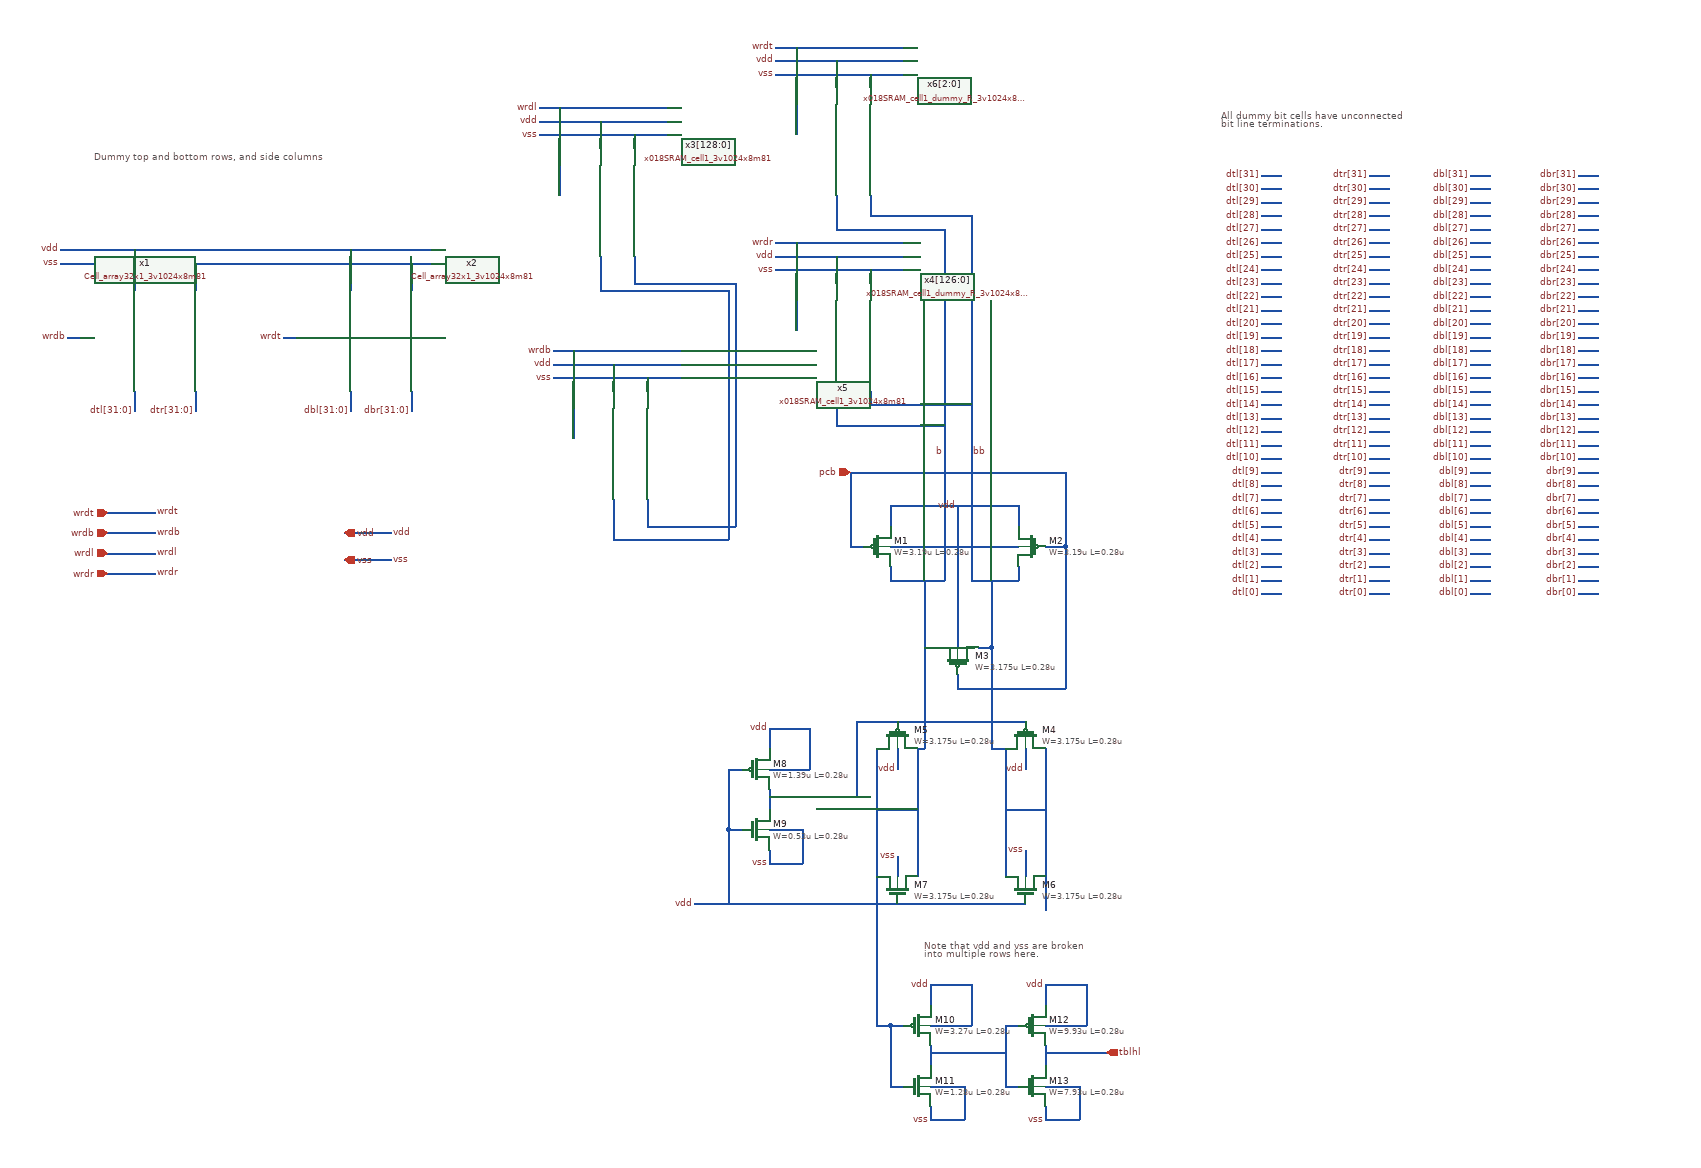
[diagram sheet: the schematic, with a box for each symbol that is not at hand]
v {xschem version=3.4.6 file_version=1.2}
G {}
K {}
V {}
S {}
E {}
T {Dummy top and bottom rows, and side columns} -160 -200 0 0 0.4 0.4 {}
T {Note that vdd and vss are broken
into multiple rows here.} 1070 970 0 0 0.3 0.3 {}
T {All dummy bit cells have unconnected
bit line terminations.} 1510 -260 0 0 0.3 0.3 {}
N 310 -30 310 10 {lab=vss}
N 220 -50 220 10 {lab=vdd}
N -10 -30 -10 10 {lab=vss}
N -100 -50 -100 10 {lab=vdd}
N -200 80 -180 80 {lab=wrdb}
N 120 80 140 80 {lab=wrdt}
N -100 160 -100 190 {lab=dtl[31:0]}
N -10 160 -10 190 {lab=dtr[31:0]}
N 220 160 220 190 {lab=dbl[31:0]}
N 310 160 310 190 {lab=dbr[31:0]}
N -140 400 -70 400 {lab=wrdl}
N 210 370 280 370 {lab=vdd}
N 210 410 280 410 {lab=vss}
N -210 -50 340 -50 {lab=vdd}
N -210 -30 340 -30 {lab=vss}
N 530 -260 530 -130 {lab=wrdl}
N 590 -240 590 -200 {lab=vdd}
N 590 -40 590 0 {lab=#net1}
N 640 -40 640 0 {lab=#net2}
N 500 -220 690 -220 {lab=vss}
N 640 -220 640 -200 {lab=vss}
N 500 -240 690 -240 {lab=vdd}
N 500 -260 690 -260 {lab=wrdl}
N 880 -60 880 70 {lab=wrdr}
N 940 -40 940 0 {lab=vdd}
N 850 -20 1040 -20 {lab=vss}
N 990 -20 990 0 {lab=vss}
N 850 -40 1040 -40 {lab=vdd}
N 850 -60 1040 -60 {lab=wrdr}
N -140 370 -70 370 {lab=wrdb}
N -140 340 -70 340 {lab=wrdt}
N 880 -350 880 -220 {lab=wrdt}
N 940 -330 940 -290 {lab=vdd}
N 850 -310 1040 -310 {lab=vss}
N 990 -310 990 -290 {lab=vss}
N 850 -330 1040 -330 {lab=vdd}
N 850 -350 1040 -350 {lab=wrdt}
N -140 430 -70 430 {lab=wrdr}
N 550 100 550 230 {lab=wrdb}
N 610 120 610 160 {lab=vdd}
N 610 320 610 360 {lab=#net1}
N 660 320 660 360 {lab=#net2}
N 520 140 710 140 {lab=vss}
N 660 140 660 160 {lab=vss}
N 520 120 710 120 {lab=vdd}
N 520 100 710 100 {lab=wrdb}
N 990 -130 990 -100 {lab=bb}
N 990 -100 1140 -100 {lab=bb}
N 1140 -100 1140 300 {lab=bb}
N 940 -130 940 -80 {lab=b}
N 940 -80 1100 -80 {lab=b}
N 1100 -80 1100 300 {lab=b}
N 990 160 990 180 {lab=bb}
N 990 180 1140 180 {lab=bb}
N 940 160 940 210 {lab=b}
N 940 210 1100 210 {lab=b}
N 1020 390 1210 390 {lab=vdd}
N 1210 420 1210 440 {lab=bb}
N 1140 440 1210 440 {lab=bb}
N 1020 420 1020 440 {lab=b}
N 1020 440 1100 440 {lab=b}
N 1210 330 1210 360 {lab=vdd}
N 1020 330 1210 330 {lab=vdd}
N 1020 330 1020 360 {lab=vdd}
N 1120 330 1120 390 {lab=vdd}
N 1250 390 1280 390 {lab=pcb}
N 1280 280 1280 390 {lab=pcb}
N 960 280 1280 280 {lab=pcb}
N 960 390 980 390 {lab=pcb}
N 960 280 960 390 {lab=pcb}
N 1140 300 1140 440 {lab=bb}
N 1100 300 1100 440 {lab=b}
N 1150 540 1170 540 {lab=bb}
N 1170 440 1170 540 {lab=bb}
N 1120 580 1120 600 {lab=pcb}
N 1120 600 1280 600 {lab=pcb}
N 1280 390 1280 600 {lab=pcb}
N 1120 390 1120 540 {lab=vdd}
N 1190 690 1190 880 {lab=bb}
N 1250 690 1250 880 {lab=bb}
N 1060 690 1060 880 {lab=b}
N 1000 690 1000 880 {lab=b}
N 1060 690 1070 690 {lab=b}
N 1170 540 1170 690 {lab=bb}
N 1170 690 1190 690 {lab=bb}
N 1070 440 1070 690 {lab=b}
N 1070 540 1090 540 {lab=b}
N 1190 780 1250 780 {lab=bb}
N 1000 880 1000 1020 {lab=b}
N 840 660 840 690 {lab=vdd}
N 840 660 900 660 {lab=vdd}
N 900 660 900 720 {lab=vdd}
N 840 720 900 720 {lab=vdd}
N 840 840 840 860 {lab=vss}
N 840 860 890 860 {lab=vss}
N 890 810 890 860 {lab=vss}
N 840 810 890 810 {lab=vss}
N 840 750 840 780 {lab=#net3}
N 780 810 800 810 {lab=vdd}
N 780 720 780 810 {lab=vdd}
N 780 720 800 720 {lab=vdd}
N 840 760 970 760 {lab=#net3}
N 970 650 970 760 {lab=#net3}
N 970 650 1220 650 {lab=#net3}
N 730 920 1220 920 {lab=vdd}
N 780 810 780 920 {lab=vdd}
N 1250 880 1250 930 {lab=bb}
N 1030 850 1030 880 {lab=vss}
N 1220 840 1220 880 {lab=vss}
N 1220 690 1220 720 {lab=vdd}
N 1030 690 1030 720 {lab=vdd}
N 1080 1040 1080 1070 {lab=vdd}
N 1080 1040 1140 1040 {lab=vdd}
N 1140 1040 1140 1100 {lab=vdd}
N 1080 1100 1140 1100 {lab=vdd}
N 1080 1220 1080 1240 {lab=vss}
N 1080 1240 1130 1240 {lab=vss}
N 1130 1190 1130 1240 {lab=vss}
N 1080 1190 1130 1190 {lab=vss}
N 1080 1130 1080 1160 {lab=#net4}
N 1020 1190 1040 1190 {lab=b}
N 1020 1100 1020 1190 {lab=b}
N 1020 1100 1040 1100 {lab=b}
N 1250 1040 1250 1070 {lab=vdd}
N 1250 1040 1310 1040 {lab=vdd}
N 1310 1040 1310 1100 {lab=vdd}
N 1250 1100 1310 1100 {lab=vdd}
N 1250 1220 1250 1240 {lab=vss}
N 1250 1240 1300 1240 {lab=vss}
N 1300 1190 1300 1240 {lab=vss}
N 1250 1190 1300 1190 {lab=vss}
N 1250 1130 1250 1160 {lab=tblhl}
N 1190 1190 1210 1190 {lab=#net4}
N 1190 1100 1190 1190 {lab=#net4}
N 1190 1100 1210 1100 {lab=#net4}
N 1080 1140 1190 1140 {lab=#net4}
N 1000 1020 1000 1100 {lab=b}
N 1000 1100 1020 1100 {lab=b}
N 1250 1140 1340 1140 {lab=tblhl}
N 1570 -160 1600 -160 {lab=dtl[31]}
N 1570 -140 1600 -140 {lab=dtl[30]}
N 1570 -120 1600 -120 {lab=dtl[29]}
N 1570 -100 1600 -100 {lab=dtl[28]}
N 1570 -80 1600 -80 {lab=dtl[27]}
N 1570 -60 1600 -60 {lab=dtl[26]}
N 1570 -40 1600 -40 {lab=dtl[25]}
N 1570 -20 1600 -20 {lab=dtl[24]}
N 1570 0 1600 0 {lab=dtl[23]}
N 1570 20 1600 20 {lab=dtl[22]}
N 1570 40 1600 40 {lab=dtl[21]}
N 1570 60 1600 60 {lab=dtl[20]}
N 1570 80 1600 80 {lab=dtl[19]}
N 1570 100 1600 100 {lab=dtl[18]}
N 1570 120 1600 120 {lab=dtl[17]}
N 1570 140 1600 140 {lab=dtl[16]}
N 1570 160 1600 160 {lab=dtl[15]}
N 1570 180 1600 180 {lab=dtl[14]}
N 1570 200 1600 200 {lab=dtl[13]}
N 1570 220 1600 220 {lab=dtl[12]}
N 1570 240 1600 240 {lab=dtl[11]}
N 1570 260 1600 260 {lab=dtl[10]}
N 1570 280 1600 280 {lab=dtl[9]}
N 1570 300 1600 300 {lab=dtl[8]}
N 1570 320 1600 320 {lab=dtl[7]}
N 1570 340 1600 340 {lab=dtl[6]}
N 1570 360 1600 360 {lab=dtl[5]}
N 1570 380 1600 380 {lab=dtl[4]}
N 1570 400 1600 400 {lab=dtl[3]}
N 1570 420 1600 420 {lab=dtl[2]}
N 1570 440 1600 440 {lab=dtl[1]}
N 1570 460 1600 460 {lab=dtl[0]}
N 1730 -160 1760 -160 {lab=dtr[31]}
N 1730 -140 1760 -140 {lab=dtr[30]}
N 1730 -120 1760 -120 {lab=dtr[29]}
N 1730 -100 1760 -100 {lab=dtr[28]}
N 1730 -80 1760 -80 {lab=dtr[27]}
N 1730 -60 1760 -60 {lab=dtr[26]}
N 1730 -40 1760 -40 {lab=dtr[25]}
N 1730 -20 1760 -20 {lab=dtr[24]}
N 1730 0 1760 0 {lab=dtr[23]}
N 1730 20 1760 20 {lab=dtr[22]}
N 1730 40 1760 40 {lab=dtr[21]}
N 1730 60 1760 60 {lab=dtr[20]}
N 1730 80 1760 80 {lab=dtr[19]}
N 1730 100 1760 100 {lab=dtr[18]}
N 1730 120 1760 120 {lab=dtr[17]}
N 1730 140 1760 140 {lab=dtr[16]}
N 1730 160 1760 160 {lab=dtr[15]}
N 1730 180 1760 180 {lab=dtr[14]}
N 1730 200 1760 200 {lab=dtr[13]}
N 1730 220 1760 220 {lab=dtr[12]}
N 1730 240 1760 240 {lab=dtr[11]}
N 1730 260 1760 260 {lab=dtr[10]}
N 1730 280 1760 280 {lab=dtr[9]}
N 1730 300 1760 300 {lab=dtr[8]}
N 1730 320 1760 320 {lab=dtr[7]}
N 1730 340 1760 340 {lab=dtr[6]}
N 1730 360 1760 360 {lab=dtr[5]}
N 1730 380 1760 380 {lab=dtr[4]}
N 1730 400 1760 400 {lab=dtr[3]}
N 1730 420 1760 420 {lab=dtr[2]}
N 1730 440 1760 440 {lab=dtr[1]}
N 1730 460 1760 460 {lab=dtr[0]}
N 1880 -160 1910 -160 {lab=dbl[31]}
N 1880 -140 1910 -140 {lab=dbl[30]}
N 1880 -120 1910 -120 {lab=dbl[29]}
N 1880 -100 1910 -100 {lab=dbl[28]}
N 1880 -80 1910 -80 {lab=dbl[27]}
N 1880 -60 1910 -60 {lab=dbl[26]}
N 1880 -40 1910 -40 {lab=dbl[25]}
N 1880 -20 1910 -20 {lab=dbl[24]}
N 1880 0 1910 0 {lab=dbl[23]}
N 1880 20 1910 20 {lab=dbl[22]}
N 1880 40 1910 40 {lab=dbl[21]}
N 1880 60 1910 60 {lab=dbl[20]}
N 1880 80 1910 80 {lab=dbl[19]}
N 1880 100 1910 100 {lab=dbl[18]}
N 1880 120 1910 120 {lab=dbl[17]}
N 1880 140 1910 140 {lab=dbl[16]}
N 1880 160 1910 160 {lab=dbl[15]}
N 1880 180 1910 180 {lab=dbl[14]}
N 1880 200 1910 200 {lab=dbl[13]}
N 1880 220 1910 220 {lab=dbl[12]}
N 1880 240 1910 240 {lab=dbl[11]}
N 1880 260 1910 260 {lab=dbl[10]}
N 1880 280 1910 280 {lab=dbl[9]}
N 1880 300 1910 300 {lab=dbl[8]}
N 1880 320 1910 320 {lab=dbl[7]}
N 1880 340 1910 340 {lab=dbl[6]}
N 1880 360 1910 360 {lab=dbl[5]}
N 1880 380 1910 380 {lab=dbl[4]}
N 1880 400 1910 400 {lab=dbl[3]}
N 1880 420 1910 420 {lab=dbl[2]}
N 1880 440 1910 440 {lab=dbl[1]}
N 1880 460 1910 460 {lab=dbl[0]}
N 2040 -160 2070 -160 {lab=dbr[31]}
N 2040 -140 2070 -140 {lab=dbr[30]}
N 2040 -120 2070 -120 {lab=dbr[29]}
N 2040 -100 2070 -100 {lab=dbr[28]}
N 2040 -80 2070 -80 {lab=dbr[27]}
N 2040 -60 2070 -60 {lab=dbr[26]}
N 2040 -40 2070 -40 {lab=dbr[25]}
N 2040 -20 2070 -20 {lab=dbr[24]}
N 2040 0 2070 0 {lab=dbr[23]}
N 2040 20 2070 20 {lab=dbr[22]}
N 2040 40 2070 40 {lab=dbr[21]}
N 2040 60 2070 60 {lab=dbr[20]}
N 2040 80 2070 80 {lab=dbr[19]}
N 2040 100 2070 100 {lab=dbr[18]}
N 2040 120 2070 120 {lab=dbr[17]}
N 2040 140 2070 140 {lab=dbr[16]}
N 2040 160 2070 160 {lab=dbr[15]}
N 2040 180 2070 180 {lab=dbr[14]}
N 2040 200 2070 200 {lab=dbr[13]}
N 2040 220 2070 220 {lab=dbr[12]}
N 2040 240 2070 240 {lab=dbr[11]}
N 2040 260 2070 260 {lab=dbr[10]}
N 2040 280 2070 280 {lab=dbr[9]}
N 2040 300 2070 300 {lab=dbr[8]}
N 2040 320 2070 320 {lab=dbr[7]}
N 2040 340 2070 340 {lab=dbr[6]}
N 2040 360 2070 360 {lab=dbr[5]}
N 2040 380 2070 380 {lab=dbr[4]}
N 2040 400 2070 400 {lab=dbr[3]}
N 2040 420 2070 420 {lab=dbr[2]}
N 2040 440 2070 440 {lab=dbr[1]}
N 2040 460 2070 460 {lab=dbr[0]}
N 640 0 790 -0 {lab=#net2}
N 790 -0 790 360 {lab=#net2}
N 660 360 790 360 {lab=#net2}
N 590 0 590 10 {lab=#net1}
N 590 10 780 10 {lab=#net1}
N 780 10 780 380 {lab=#net1}
N 610 380 780 380 {lab=#net1}
N 610 360 610 380 {lab=#net1}
N 1000 780 1060 780 {lab=b}
C {Cell_array32x1_3v1024x8m81.sym} -50 80 0 0 {name=x1}
C {Cell_array32x1_3v1024x8m81.sym} 270 80 0 0 {name=x2}
C {lab_pin.sym} -100 190 3 0 {name=p1 sig_type=std_logic lab=dtl[31:0]}
C {lab_pin.sym} -10 190 3 0 {name=p2 sig_type=std_logic lab=dtr[31:0]}
C {lab_pin.sym} 220 190 3 0 {name=p3 sig_type=std_logic lab=dbl[31:0]}
C {lab_pin.sym} 310 190 3 0 {name=p4 sig_type=std_logic lab=dbr[31:0]}
C {lab_pin.sym} -210 -50 0 0 {name=p97 sig_type=std_logic lab=vdd}
C {lab_pin.sym} -210 -30 0 0 {name=p98 sig_type=std_logic lab=vss}
C {ipin.sym} -140 400 0 0 {name=p105 lab=wrdl}
C {iopin.sym} 210 370 0 1 {name=p108 lab=vdd}
C {iopin.sym} 210 410 0 1 {name=p109 lab=vss}
C {lab_pin.sym} 280 410 0 1 {name=p110 sig_type=std_logic lab=vss}
C {lab_pin.sym} 280 370 0 1 {name=p111 sig_type=std_logic lab=vdd}
C {lab_pin.sym} -70 400 0 1 {name=p114 sig_type=std_logic lab=wrdl}
C {x018SRAM_cell1_3v1024x8m81.sym} 680 -150 0 0 {name=x3[128:0]}
C {lab_pin.sym} 500 -220 0 0 {name=p5 sig_type=std_logic lab=vss}
C {lab_pin.sym} 500 -240 0 0 {name=p6 sig_type=std_logic lab=vdd}
C {lab_pin.sym} 500 -260 0 0 {name=p9 sig_type=std_logic lab=wrdl}
C {lab_pin.sym} -200 80 0 0 {name=p10 sig_type=std_logic lab=wrdb}
C {lab_pin.sym} 850 -20 0 0 {name=p19 sig_type=std_logic lab=vss}
C {lab_pin.sym} 850 -40 0 0 {name=p20 sig_type=std_logic lab=vdd}
C {lab_pin.sym} 850 -60 0 0 {name=p23 sig_type=std_logic lab=wrdr}
C {x018SRAM_cell1_dummy_R_3v1024x8m81.sym} 1030 50 0 0 {name=x4[126:0]}
C {lab_pin.sym} 120 80 0 0 {name=p24 sig_type=std_logic lab=wrdt}
C {ipin.sym} -140 370 0 0 {name=p25 lab=wrdb}
C {lab_pin.sym} -70 370 0 1 {name=p26 sig_type=std_logic lab=wrdb}
C {ipin.sym} -140 340 0 0 {name=p27 lab=wrdt}
C {lab_pin.sym} -70 340 0 1 {name=p28 sig_type=std_logic lab=wrdt}
C {lab_pin.sym} 850 -310 0 0 {name=p21 sig_type=std_logic lab=vss}
C {lab_pin.sym} 850 -330 0 0 {name=p22 sig_type=std_logic lab=vdd}
C {lab_pin.sym} 850 -350 0 0 {name=p29 sig_type=std_logic lab=wrdt}
C {x018SRAM_cell1_dummy_R_3v1024x8m81.sym} 1030 -240 0 0 {name=x6[2:0]}
C {ipin.sym} -140 430 0 0 {name=p30 lab=wrdr}
C {lab_pin.sym} -70 430 0 1 {name=p31 sig_type=std_logic lab=wrdr}
C {x018SRAM_cell1_3v1024x8m81.sym} 700 210 0 0 {name=x5}
C {lab_pin.sym} 520 140 0 0 {name=p32 sig_type=std_logic lab=vss}
C {lab_pin.sym} 520 120 0 0 {name=p33 sig_type=std_logic lab=vdd}
C {lab_pin.sym} 520 100 0 0 {name=p36 sig_type=std_logic lab=wrdb}
C {ipin.sym} 960 280 0 0 {name=p37 lab=pcb}
C {lab_pin.sym} 1100 250 0 0 {name=p38 sig_type=std_logic lab=b}
C {lab_pin.sym} 1140 250 0 1 {name=p39 sig_type=std_logic lab=bb}
C {symbols/pfet_03v3.sym} 1000 390 0 0 {name=M1
L=0.28u
W=3.19u
nf=2
m=1
ad="'int((nf+1)/2) * W/nf * 0.18u'"
pd="'2*int((nf+1)/2) * (W/nf + 0.18u)'"
as="'int((nf+2)/2) * W/nf * 0.18u'"
ps="'2*int((nf+2)/2) * (W/nf + 0.18u)'"
nrd="'0.18u / W'" nrs="'0.18u / W'"
sa=0 sb=0 sd=0
model=pfet_03v3
spiceprefix=X
}
C {symbols/pfet_03v3.sym} 1230 390 0 1 {name=M2
L=0.28u
W=3.19u
nf=2
m=1
ad="'int((nf+1)/2) * W/nf * 0.18u'"
pd="'2*int((nf+1)/2) * (W/nf + 0.18u)'"
as="'int((nf+2)/2) * W/nf * 0.18u'"
ps="'2*int((nf+2)/2) * (W/nf + 0.18u)'"
nrd="'0.18u / W'" nrs="'0.18u / W'"
sa=0 sb=0 sd=0
model=pfet_03v3
spiceprefix=X
}
C {lab_pin.sym} 1120 330 1 0 {name=p40 sig_type=std_logic lab=vdd}
C {symbols/pfet_03v3.sym} 1120 560 3 0 {name=M3
L=0.28u
W=3.175u
nf=1
m=1
ad="'int((nf+1)/2) * W/nf * 0.18u'"
pd="'2*int((nf+1)/2) * (W/nf + 0.18u)'"
as="'int((nf+2)/2) * W/nf * 0.18u'"
ps="'2*int((nf+2)/2) * (W/nf + 0.18u)'"
nrd="'0.18u / W'" nrs="'0.18u / W'"
sa=0 sb=0 sd=0
model=pfet_03v3
spiceprefix=X
}
C {symbols/pfet_03v3.sym} 1220 670 3 1 {name=M4
L=0.28u
W=3.175u
nf=1
m=1
ad="'int((nf+1)/2) * W/nf * 0.18u'"
pd="'2*int((nf+1)/2) * (W/nf + 0.18u)'"
as="'int((nf+2)/2) * W/nf * 0.18u'"
ps="'2*int((nf+2)/2) * (W/nf + 0.18u)'"
nrd="'0.18u / W'" nrs="'0.18u / W'"
sa=0 sb=0 sd=0
model=pfet_03v3
spiceprefix=X
}
C {symbols/pfet_03v3.sym} 1030 670 3 1 {name=M5
L=0.28u
W=3.175u
nf=1
m=1
ad="'int((nf+1)/2) * W/nf * 0.18u'"
pd="'2*int((nf+1)/2) * (W/nf + 0.18u)'"
as="'int((nf+2)/2) * W/nf * 0.18u'"
ps="'2*int((nf+2)/2) * (W/nf + 0.18u)'"
nrd="'0.18u / W'" nrs="'0.18u / W'"
sa=0 sb=0 sd=0
model=pfet_03v3
spiceprefix=X
}
C {symbols/nfet_03v3.sym} 1220 900 3 0 {name=M6
L=0.28u
W=3.175u
nf=1
m=1
ad="'int((nf+1)/2) * W/nf * 0.18u'"
pd="'2*int((nf+1)/2) * (W/nf + 0.18u)'"
as="'int((nf+2)/2) * W/nf * 0.18u'"
ps="'2*int((nf+2)/2) * (W/nf + 0.18u)'"
nrd="'0.18u / W'" nrs="'0.18u / W'"
sa=0 sb=0 sd=0
model=nfet_03v3
spiceprefix=X
}
C {symbols/nfet_03v3.sym} 1030 900 3 0 {name=M7
L=0.28u
W=3.175u
nf=1
m=1
ad="'int((nf+1)/2) * W/nf * 0.18u'"
pd="'2*int((nf+1)/2) * (W/nf + 0.18u)'"
as="'int((nf+2)/2) * W/nf * 0.18u'"
ps="'2*int((nf+2)/2) * (W/nf + 0.18u)'"
nrd="'0.18u / W'" nrs="'0.18u / W'"
sa=0 sb=0 sd=0
model=nfet_03v3
spiceprefix=X
}
C {lab_pin.sym} 730 920 0 0 {name=p41 sig_type=std_logic lab=vdd}
C {symbols/pfet_03v3.sym} 820 720 2 1 {name=M8
L=0.28u
W=1.39u
nf=2
m=1
ad="'int((nf+1)/2) * W/nf * 0.18u'"
pd="'2*int((nf+1)/2) * (W/nf + 0.18u)'"
as="'int((nf+2)/2) * W/nf * 0.18u'"
ps="'2*int((nf+2)/2) * (W/nf + 0.18u)'"
nrd="'0.18u / W'" nrs="'0.18u / W'"
sa=0 sb=0 sd=0
model=pfet_03v3
spiceprefix=X
}
C {symbols/nfet_03v3.sym} 820 810 0 0 {name=M9
L=0.28u
W=0.53u
nf=2
m=1
ad="'int((nf+1)/2) * W/nf * 0.18u'"
pd="'2*int((nf+1)/2) * (W/nf + 0.18u)'"
as="'int((nf+2)/2) * W/nf * 0.18u'"
ps="'2*int((nf+2)/2) * (W/nf + 0.18u)'"
nrd="'0.18u / W'" nrs="'0.18u / W'"
sa=0 sb=0 sd=0
model=nfet_03v3
spiceprefix=X
}
C {lab_pin.sym} 840 660 0 0 {name=p42 sig_type=std_logic lab=vdd}
C {lab_pin.sym} 840 860 0 0 {name=p43 sig_type=std_logic lab=vss}
C {noconn.sym} 1250 930 3 0 {name=l1}
C {lab_pin.sym} 1030 720 3 0 {name=p44 sig_type=std_logic lab=vdd}
C {lab_pin.sym} 1220 720 3 0 {name=p45 sig_type=std_logic lab=vdd}
C {lab_pin.sym} 1030 850 1 0 {name=p46 sig_type=std_logic lab=vss}
C {lab_pin.sym} 1220 840 1 0 {name=p47 sig_type=std_logic lab=vss}
C {symbols/pfet_03v3.sym} 1060 1100 2 1 {name=M10
L=0.28u
W=3.27u
nf=2
m=1
ad="'int((nf+1)/2) * W/nf * 0.18u'"
pd="'2*int((nf+1)/2) * (W/nf + 0.18u)'"
as="'int((nf+2)/2) * W/nf * 0.18u'"
ps="'2*int((nf+2)/2) * (W/nf + 0.18u)'"
nrd="'0.18u / W'" nrs="'0.18u / W'"
sa=0 sb=0 sd=0
model=pfet_03v3
spiceprefix=X
}
C {symbols/nfet_03v3.sym} 1060 1190 0 0 {name=M11
L=0.28u
W=1.28u
nf=2
m=1
ad="'int((nf+1)/2) * W/nf * 0.18u'"
pd="'2*int((nf+1)/2) * (W/nf + 0.18u)'"
as="'int((nf+2)/2) * W/nf * 0.18u'"
ps="'2*int((nf+2)/2) * (W/nf + 0.18u)'"
nrd="'0.18u / W'" nrs="'0.18u / W'"
sa=0 sb=0 sd=0
model=nfet_03v3
spiceprefix=X
}
C {lab_pin.sym} 1080 1040 0 0 {name=p48 sig_type=std_logic lab=vdd}
C {lab_pin.sym} 1080 1240 0 0 {name=p49 sig_type=std_logic lab=vss}
C {symbols/pfet_03v3.sym} 1230 1100 2 1 {name=M12
L=0.28u
W=9.93u
nf=2
m=1
ad="'int((nf+1)/2) * W/nf * 0.18u'"
pd="'2*int((nf+1)/2) * (W/nf + 0.18u)'"
as="'int((nf+2)/2) * W/nf * 0.18u'"
ps="'2*int((nf+2)/2) * (W/nf + 0.18u)'"
nrd="'0.18u / W'" nrs="'0.18u / W'"
sa=0 sb=0 sd=0
model=pfet_03v3
spiceprefix=X
}
C {symbols/nfet_03v3.sym} 1230 1190 0 0 {name=M13
L=0.28u
W=7.93u
nf=2
m=1
ad="'int((nf+1)/2) * W/nf * 0.18u'"
pd="'2*int((nf+1)/2) * (W/nf + 0.18u)'"
as="'int((nf+2)/2) * W/nf * 0.18u'"
ps="'2*int((nf+2)/2) * (W/nf + 0.18u)'"
nrd="'0.18u / W'" nrs="'0.18u / W'"
sa=0 sb=0 sd=0
model=nfet_03v3
spiceprefix=X
}
C {lab_pin.sym} 1250 1040 0 0 {name=p50 sig_type=std_logic lab=vdd}
C {lab_pin.sym} 1250 1240 0 0 {name=p51 sig_type=std_logic lab=vss}
C {opin.sym} 1340 1140 0 0 {name=p52 lab=tblhl}
C {noconn.sym} 1600 -160 0 1 {name=l4}
C {noconn.sym} 1600 -140 0 1 {name=l5}
C {noconn.sym} 1600 -120 0 1 {name=l6}
C {noconn.sym} 1600 -100 0 1 {name=l7}
C {noconn.sym} 1600 -80 0 1 {name=l8}
C {noconn.sym} 1600 -60 0 1 {name=l9}
C {noconn.sym} 1600 -40 0 1 {name=l10}
C {noconn.sym} 1600 -20 0 1 {name=l11}
C {noconn.sym} 1600 0 0 1 {name=l12}
C {noconn.sym} 1600 20 0 1 {name=l13}
C {noconn.sym} 1600 40 0 1 {name=l14}
C {noconn.sym} 1600 60 0 1 {name=l15}
C {noconn.sym} 1600 80 0 1 {name=l16}
C {noconn.sym} 1600 100 0 1 {name=l17}
C {noconn.sym} 1600 120 0 1 {name=l18}
C {noconn.sym} 1600 140 0 1 {name=l19}
C {noconn.sym} 1600 160 0 1 {name=l20}
C {noconn.sym} 1600 180 0 1 {name=l21}
C {noconn.sym} 1600 200 0 1 {name=l22}
C {noconn.sym} 1600 220 0 1 {name=l23}
C {noconn.sym} 1600 240 0 1 {name=l24}
C {noconn.sym} 1600 260 0 1 {name=l25}
C {noconn.sym} 1600 280 0 1 {name=l26}
C {noconn.sym} 1600 300 0 1 {name=l27}
C {noconn.sym} 1600 320 0 1 {name=l28}
C {noconn.sym} 1600 340 0 1 {name=l29}
C {noconn.sym} 1600 360 0 1 {name=l30}
C {noconn.sym} 1600 380 0 1 {name=l31}
C {noconn.sym} 1600 400 0 1 {name=l32}
C {noconn.sym} 1600 420 0 1 {name=l33}
C {noconn.sym} 1600 440 0 1 {name=l34}
C {noconn.sym} 1600 460 0 1 {name=l35}
C {lab_pin.sym} 1570 -160 0 0 {name=p61 sig_type=std_logic lab=dtl[31]}
C {lab_pin.sym} 1570 -140 0 0 {name=p62 sig_type=std_logic lab=dtl[30]}
C {lab_pin.sym} 1570 -120 0 0 {name=p63 sig_type=std_logic lab=dtl[29]}
C {lab_pin.sym} 1570 -100 0 0 {name=p64 sig_type=std_logic lab=dtl[28]}
C {lab_pin.sym} 1570 -80 0 0 {name=p65 sig_type=std_logic lab=dtl[27]}
C {lab_pin.sym} 1570 -60 0 0 {name=p66 sig_type=std_logic lab=dtl[26]}
C {lab_pin.sym} 1570 -40 0 0 {name=p67 sig_type=std_logic lab=dtl[25]}
C {lab_pin.sym} 1570 -20 0 0 {name=p68 sig_type=std_logic lab=dtl[24]}
C {lab_pin.sym} 1570 0 0 0 {name=p69 sig_type=std_logic lab=dtl[23]}
C {lab_pin.sym} 1570 20 0 0 {name=p70 sig_type=std_logic lab=dtl[22]}
C {lab_pin.sym} 1570 40 0 0 {name=p71 sig_type=std_logic lab=dtl[21]}
C {lab_pin.sym} 1570 60 0 0 {name=p72 sig_type=std_logic lab=dtl[20]}
C {lab_pin.sym} 1570 80 0 0 {name=p73 sig_type=std_logic lab=dtl[19]}
C {lab_pin.sym} 1570 100 0 0 {name=p74 sig_type=std_logic lab=dtl[18]}
C {lab_pin.sym} 1570 120 0 0 {name=p75 sig_type=std_logic lab=dtl[17]}
C {lab_pin.sym} 1570 140 0 0 {name=p76 sig_type=std_logic lab=dtl[16]}
C {lab_pin.sym} 1570 160 0 0 {name=p77 sig_type=std_logic lab=dtl[15]}
C {lab_pin.sym} 1570 180 0 0 {name=p78 sig_type=std_logic lab=dtl[14]}
C {lab_pin.sym} 1570 200 0 0 {name=p79 sig_type=std_logic lab=dtl[13]}
C {lab_pin.sym} 1570 220 0 0 {name=p80 sig_type=std_logic lab=dtl[12]}
C {lab_pin.sym} 1570 240 0 0 {name=p81 sig_type=std_logic lab=dtl[11]}
C {lab_pin.sym} 1570 260 0 0 {name=p82 sig_type=std_logic lab=dtl[10]}
C {lab_pin.sym} 1570 280 0 0 {name=p83 sig_type=std_logic lab=dtl[9]}
C {lab_pin.sym} 1570 300 0 0 {name=p84 sig_type=std_logic lab=dtl[8]}
C {lab_pin.sym} 1570 320 0 0 {name=p85 sig_type=std_logic lab=dtl[7]}
C {lab_pin.sym} 1570 340 0 0 {name=p86 sig_type=std_logic lab=dtl[6]}
C {lab_pin.sym} 1570 360 0 0 {name=p87 sig_type=std_logic lab=dtl[5]}
C {lab_pin.sym} 1570 380 0 0 {name=p88 sig_type=std_logic lab=dtl[4]}
C {lab_pin.sym} 1570 400 0 0 {name=p89 sig_type=std_logic lab=dtl[3]}
C {lab_pin.sym} 1570 420 0 0 {name=p90 sig_type=std_logic lab=dtl[2]}
C {lab_pin.sym} 1570 440 0 0 {name=p91 sig_type=std_logic lab=dtl[1]}
C {lab_pin.sym} 1570 460 0 0 {name=p92 sig_type=std_logic lab=dtl[0]}
C {noconn.sym} 1760 -160 0 1 {name=l36}
C {noconn.sym} 1760 -140 0 1 {name=l37}
C {noconn.sym} 1760 -120 0 1 {name=l38}
C {noconn.sym} 1760 -100 0 1 {name=l39}
C {noconn.sym} 1760 -80 0 1 {name=l40}
C {noconn.sym} 1760 -60 0 1 {name=l41}
C {noconn.sym} 1760 -40 0 1 {name=l42}
C {noconn.sym} 1760 -20 0 1 {name=l43}
C {noconn.sym} 1760 0 0 1 {name=l44}
C {noconn.sym} 1760 20 0 1 {name=l45}
C {noconn.sym} 1760 40 0 1 {name=l46}
C {noconn.sym} 1760 60 0 1 {name=l47}
C {noconn.sym} 1760 80 0 1 {name=l48}
C {noconn.sym} 1760 100 0 1 {name=l49}
C {noconn.sym} 1760 120 0 1 {name=l50}
C {noconn.sym} 1760 140 0 1 {name=l51}
C {noconn.sym} 1760 160 0 1 {name=l52}
C {noconn.sym} 1760 180 0 1 {name=l53}
C {noconn.sym} 1760 200 0 1 {name=l54}
C {noconn.sym} 1760 220 0 1 {name=l55}
C {noconn.sym} 1760 240 0 1 {name=l56}
C {noconn.sym} 1760 260 0 1 {name=l57}
C {noconn.sym} 1760 280 0 1 {name=l58}
C {noconn.sym} 1760 300 0 1 {name=l59}
C {noconn.sym} 1760 320 0 1 {name=l60}
C {noconn.sym} 1760 340 0 1 {name=l61}
C {noconn.sym} 1760 360 0 1 {name=l62}
C {noconn.sym} 1760 380 0 1 {name=l63}
C {noconn.sym} 1760 400 0 1 {name=l64}
C {noconn.sym} 1760 420 0 1 {name=l65}
C {noconn.sym} 1760 440 0 1 {name=l66}
C {noconn.sym} 1760 460 0 1 {name=l67}
C {lab_pin.sym} 1730 -160 0 0 {name=p93 sig_type=std_logic lab=dtr[31]}
C {lab_pin.sym} 1730 -140 0 0 {name=p94 sig_type=std_logic lab=dtr[30]}
C {lab_pin.sym} 1730 -120 0 0 {name=p95 sig_type=std_logic lab=dtr[29]}
C {lab_pin.sym} 1730 -100 0 0 {name=p96 sig_type=std_logic lab=dtr[28]}
C {lab_pin.sym} 1730 -80 0 0 {name=p99 sig_type=std_logic lab=dtr[27]}
C {lab_pin.sym} 1730 -60 0 0 {name=p100 sig_type=std_logic lab=dtr[26]}
C {lab_pin.sym} 1730 -40 0 0 {name=p101 sig_type=std_logic lab=dtr[25]}
C {lab_pin.sym} 1730 -20 0 0 {name=p102 sig_type=std_logic lab=dtr[24]}
C {lab_pin.sym} 1730 0 0 0 {name=p103 sig_type=std_logic lab=dtr[23]}
C {lab_pin.sym} 1730 20 0 0 {name=p104 sig_type=std_logic lab=dtr[22]}
C {lab_pin.sym} 1730 40 0 0 {name=p106 sig_type=std_logic lab=dtr[21]}
C {lab_pin.sym} 1730 60 0 0 {name=p107 sig_type=std_logic lab=dtr[20]}
C {lab_pin.sym} 1730 80 0 0 {name=p112 sig_type=std_logic lab=dtr[19]}
C {lab_pin.sym} 1730 100 0 0 {name=p113 sig_type=std_logic lab=dtr[18]}
C {lab_pin.sym} 1730 120 0 0 {name=p115 sig_type=std_logic lab=dtr[17]}
C {lab_pin.sym} 1730 140 0 0 {name=p116 sig_type=std_logic lab=dtr[16]}
C {lab_pin.sym} 1730 160 0 0 {name=p117 sig_type=std_logic lab=dtr[15]}
C {lab_pin.sym} 1730 180 0 0 {name=p118 sig_type=std_logic lab=dtr[14]}
C {lab_pin.sym} 1730 200 0 0 {name=p119 sig_type=std_logic lab=dtr[13]}
C {lab_pin.sym} 1730 220 0 0 {name=p120 sig_type=std_logic lab=dtr[12]}
C {lab_pin.sym} 1730 240 0 0 {name=p121 sig_type=std_logic lab=dtr[11]}
C {lab_pin.sym} 1730 260 0 0 {name=p122 sig_type=std_logic lab=dtr[10]}
C {lab_pin.sym} 1730 280 0 0 {name=p123 sig_type=std_logic lab=dtr[9]}
C {lab_pin.sym} 1730 300 0 0 {name=p124 sig_type=std_logic lab=dtr[8]}
C {lab_pin.sym} 1730 320 0 0 {name=p125 sig_type=std_logic lab=dtr[7]}
C {lab_pin.sym} 1730 340 0 0 {name=p126 sig_type=std_logic lab=dtr[6]}
C {lab_pin.sym} 1730 360 0 0 {name=p127 sig_type=std_logic lab=dtr[5]}
C {lab_pin.sym} 1730 380 0 0 {name=p128 sig_type=std_logic lab=dtr[4]}
C {lab_pin.sym} 1730 400 0 0 {name=p129 sig_type=std_logic lab=dtr[3]}
C {lab_pin.sym} 1730 420 0 0 {name=p130 sig_type=std_logic lab=dtr[2]}
C {lab_pin.sym} 1730 440 0 0 {name=p131 sig_type=std_logic lab=dtr[1]}
C {lab_pin.sym} 1730 460 0 0 {name=p132 sig_type=std_logic lab=dtr[0]}
C {noconn.sym} 1910 -160 0 1 {name=l68}
C {noconn.sym} 1910 -140 0 1 {name=l69}
C {noconn.sym} 1910 -120 0 1 {name=l70}
C {noconn.sym} 1910 -100 0 1 {name=l71}
C {noconn.sym} 1910 -80 0 1 {name=l72}
C {noconn.sym} 1910 -60 0 1 {name=l73}
C {noconn.sym} 1910 -40 0 1 {name=l74}
C {noconn.sym} 1910 -20 0 1 {name=l75}
C {noconn.sym} 1910 0 0 1 {name=l76}
C {noconn.sym} 1910 20 0 1 {name=l77}
C {noconn.sym} 1910 40 0 1 {name=l78}
C {noconn.sym} 1910 60 0 1 {name=l79}
C {noconn.sym} 1910 80 0 1 {name=l80}
C {noconn.sym} 1910 100 0 1 {name=l81}
C {noconn.sym} 1910 120 0 1 {name=l82}
C {noconn.sym} 1910 140 0 1 {name=l83}
C {noconn.sym} 1910 160 0 1 {name=l84}
C {noconn.sym} 1910 180 0 1 {name=l85}
C {noconn.sym} 1910 200 0 1 {name=l86}
C {noconn.sym} 1910 220 0 1 {name=l87}
C {noconn.sym} 1910 240 0 1 {name=l88}
C {noconn.sym} 1910 260 0 1 {name=l89}
C {noconn.sym} 1910 280 0 1 {name=l90}
C {noconn.sym} 1910 300 0 1 {name=l91}
C {noconn.sym} 1910 320 0 1 {name=l92}
C {noconn.sym} 1910 340 0 1 {name=l93}
C {noconn.sym} 1910 360 0 1 {name=l94}
C {noconn.sym} 1910 380 0 1 {name=l95}
C {noconn.sym} 1910 400 0 1 {name=l96}
C {noconn.sym} 1910 420 0 1 {name=l97}
C {noconn.sym} 1910 440 0 1 {name=l98}
C {noconn.sym} 1910 460 0 1 {name=l99}
C {lab_pin.sym} 1880 -160 0 0 {name=p133 sig_type=std_logic lab=dbl[31]}
C {lab_pin.sym} 1880 -140 0 0 {name=p134 sig_type=std_logic lab=dbl[30]}
C {lab_pin.sym} 1880 -120 0 0 {name=p135 sig_type=std_logic lab=dbl[29]}
C {lab_pin.sym} 1880 -100 0 0 {name=p136 sig_type=std_logic lab=dbl[28]}
C {lab_pin.sym} 1880 -80 0 0 {name=p137 sig_type=std_logic lab=dbl[27]}
C {lab_pin.sym} 1880 -60 0 0 {name=p138 sig_type=std_logic lab=dbl[26]}
C {lab_pin.sym} 1880 -40 0 0 {name=p139 sig_type=std_logic lab=dbl[25]}
C {lab_pin.sym} 1880 -20 0 0 {name=p140 sig_type=std_logic lab=dbl[24]}
C {lab_pin.sym} 1880 0 0 0 {name=p141 sig_type=std_logic lab=dbl[23]}
C {lab_pin.sym} 1880 20 0 0 {name=p142 sig_type=std_logic lab=dbl[22]}
C {lab_pin.sym} 1880 40 0 0 {name=p143 sig_type=std_logic lab=dbl[21]}
C {lab_pin.sym} 1880 60 0 0 {name=p144 sig_type=std_logic lab=dbl[20]}
C {lab_pin.sym} 1880 80 0 0 {name=p145 sig_type=std_logic lab=dbl[19]}
C {lab_pin.sym} 1880 100 0 0 {name=p146 sig_type=std_logic lab=dbl[18]}
C {lab_pin.sym} 1880 120 0 0 {name=p147 sig_type=std_logic lab=dbl[17]}
C {lab_pin.sym} 1880 140 0 0 {name=p148 sig_type=std_logic lab=dbl[16]}
C {lab_pin.sym} 1880 160 0 0 {name=p149 sig_type=std_logic lab=dbl[15]}
C {lab_pin.sym} 1880 180 0 0 {name=p150 sig_type=std_logic lab=dbl[14]}
C {lab_pin.sym} 1880 200 0 0 {name=p151 sig_type=std_logic lab=dbl[13]}
C {lab_pin.sym} 1880 220 0 0 {name=p152 sig_type=std_logic lab=dbl[12]}
C {lab_pin.sym} 1880 240 0 0 {name=p153 sig_type=std_logic lab=dbl[11]}
C {lab_pin.sym} 1880 260 0 0 {name=p154 sig_type=std_logic lab=dbl[10]}
C {lab_pin.sym} 1880 280 0 0 {name=p155 sig_type=std_logic lab=dbl[9]}
C {lab_pin.sym} 1880 300 0 0 {name=p156 sig_type=std_logic lab=dbl[8]}
C {lab_pin.sym} 1880 320 0 0 {name=p157 sig_type=std_logic lab=dbl[7]}
C {lab_pin.sym} 1880 340 0 0 {name=p158 sig_type=std_logic lab=dbl[6]}
C {lab_pin.sym} 1880 360 0 0 {name=p159 sig_type=std_logic lab=dbl[5]}
C {lab_pin.sym} 1880 380 0 0 {name=p160 sig_type=std_logic lab=dbl[4]}
C {lab_pin.sym} 1880 400 0 0 {name=p161 sig_type=std_logic lab=dbl[3]}
C {lab_pin.sym} 1880 420 0 0 {name=p162 sig_type=std_logic lab=dbl[2]}
C {lab_pin.sym} 1880 440 0 0 {name=p163 sig_type=std_logic lab=dbl[1]}
C {lab_pin.sym} 1880 460 0 0 {name=p164 sig_type=std_logic lab=dbl[0]}
C {noconn.sym} 2070 -160 0 1 {name=l100}
C {noconn.sym} 2070 -140 0 1 {name=l101}
C {noconn.sym} 2070 -120 0 1 {name=l102}
C {noconn.sym} 2070 -100 0 1 {name=l103}
C {noconn.sym} 2070 -80 0 1 {name=l104}
C {noconn.sym} 2070 -60 0 1 {name=l105}
C {noconn.sym} 2070 -40 0 1 {name=l106}
C {noconn.sym} 2070 -20 0 1 {name=l107}
C {noconn.sym} 2070 0 0 1 {name=l108}
C {noconn.sym} 2070 20 0 1 {name=l109}
C {noconn.sym} 2070 40 0 1 {name=l110}
C {noconn.sym} 2070 60 0 1 {name=l111}
C {noconn.sym} 2070 80 0 1 {name=l112}
C {noconn.sym} 2070 100 0 1 {name=l113}
C {noconn.sym} 2070 120 0 1 {name=l114}
C {noconn.sym} 2070 140 0 1 {name=l115}
C {noconn.sym} 2070 160 0 1 {name=l116}
C {noconn.sym} 2070 180 0 1 {name=l117}
C {noconn.sym} 2070 200 0 1 {name=l118}
C {noconn.sym} 2070 220 0 1 {name=l119}
C {noconn.sym} 2070 240 0 1 {name=l120}
C {noconn.sym} 2070 260 0 1 {name=l121}
C {noconn.sym} 2070 280 0 1 {name=l122}
C {noconn.sym} 2070 300 0 1 {name=l123}
C {noconn.sym} 2070 320 0 1 {name=l124}
C {noconn.sym} 2070 340 0 1 {name=l125}
C {noconn.sym} 2070 360 0 1 {name=l126}
C {noconn.sym} 2070 380 0 1 {name=l127}
C {noconn.sym} 2070 400 0 1 {name=l128}
C {noconn.sym} 2070 420 0 1 {name=l129}
C {noconn.sym} 2070 440 0 1 {name=l130}
C {noconn.sym} 2070 460 0 1 {name=l131}
C {lab_pin.sym} 2040 -160 0 0 {name=p165 sig_type=std_logic lab=dbr[31]}
C {lab_pin.sym} 2040 -140 0 0 {name=p166 sig_type=std_logic lab=dbr[30]}
C {lab_pin.sym} 2040 -120 0 0 {name=p167 sig_type=std_logic lab=dbr[29]}
C {lab_pin.sym} 2040 -100 0 0 {name=p168 sig_type=std_logic lab=dbr[28]}
C {lab_pin.sym} 2040 -80 0 0 {name=p169 sig_type=std_logic lab=dbr[27]}
C {lab_pin.sym} 2040 -60 0 0 {name=p170 sig_type=std_logic lab=dbr[26]}
C {lab_pin.sym} 2040 -40 0 0 {name=p171 sig_type=std_logic lab=dbr[25]}
C {lab_pin.sym} 2040 -20 0 0 {name=p172 sig_type=std_logic lab=dbr[24]}
C {lab_pin.sym} 2040 0 0 0 {name=p173 sig_type=std_logic lab=dbr[23]}
C {lab_pin.sym} 2040 20 0 0 {name=p174 sig_type=std_logic lab=dbr[22]}
C {lab_pin.sym} 2040 40 0 0 {name=p175 sig_type=std_logic lab=dbr[21]}
C {lab_pin.sym} 2040 60 0 0 {name=p176 sig_type=std_logic lab=dbr[20]}
C {lab_pin.sym} 2040 80 0 0 {name=p177 sig_type=std_logic lab=dbr[19]}
C {lab_pin.sym} 2040 100 0 0 {name=p178 sig_type=std_logic lab=dbr[18]}
C {lab_pin.sym} 2040 120 0 0 {name=p179 sig_type=std_logic lab=dbr[17]}
C {lab_pin.sym} 2040 140 0 0 {name=p180 sig_type=std_logic lab=dbr[16]}
C {lab_pin.sym} 2040 160 0 0 {name=p181 sig_type=std_logic lab=dbr[15]}
C {lab_pin.sym} 2040 180 0 0 {name=p182 sig_type=std_logic lab=dbr[14]}
C {lab_pin.sym} 2040 200 0 0 {name=p183 sig_type=std_logic lab=dbr[13]}
C {lab_pin.sym} 2040 220 0 0 {name=p184 sig_type=std_logic lab=dbr[12]}
C {lab_pin.sym} 2040 240 0 0 {name=p185 sig_type=std_logic lab=dbr[11]}
C {lab_pin.sym} 2040 260 0 0 {name=p186 sig_type=std_logic lab=dbr[10]}
C {lab_pin.sym} 2040 280 0 0 {name=p187 sig_type=std_logic lab=dbr[9]}
C {lab_pin.sym} 2040 300 0 0 {name=p188 sig_type=std_logic lab=dbr[8]}
C {lab_pin.sym} 2040 320 0 0 {name=p189 sig_type=std_logic lab=dbr[7]}
C {lab_pin.sym} 2040 340 0 0 {name=p190 sig_type=std_logic lab=dbr[6]}
C {lab_pin.sym} 2040 360 0 0 {name=p191 sig_type=std_logic lab=dbr[5]}
C {lab_pin.sym} 2040 380 0 0 {name=p192 sig_type=std_logic lab=dbr[4]}
C {lab_pin.sym} 2040 400 0 0 {name=p193 sig_type=std_logic lab=dbr[3]}
C {lab_pin.sym} 2040 420 0 0 {name=p194 sig_type=std_logic lab=dbr[2]}
C {lab_pin.sym} 2040 440 0 0 {name=p195 sig_type=std_logic lab=dbr[1]}
C {lab_pin.sym} 2040 460 0 0 {name=p196 sig_type=std_logic lab=dbr[0]}
